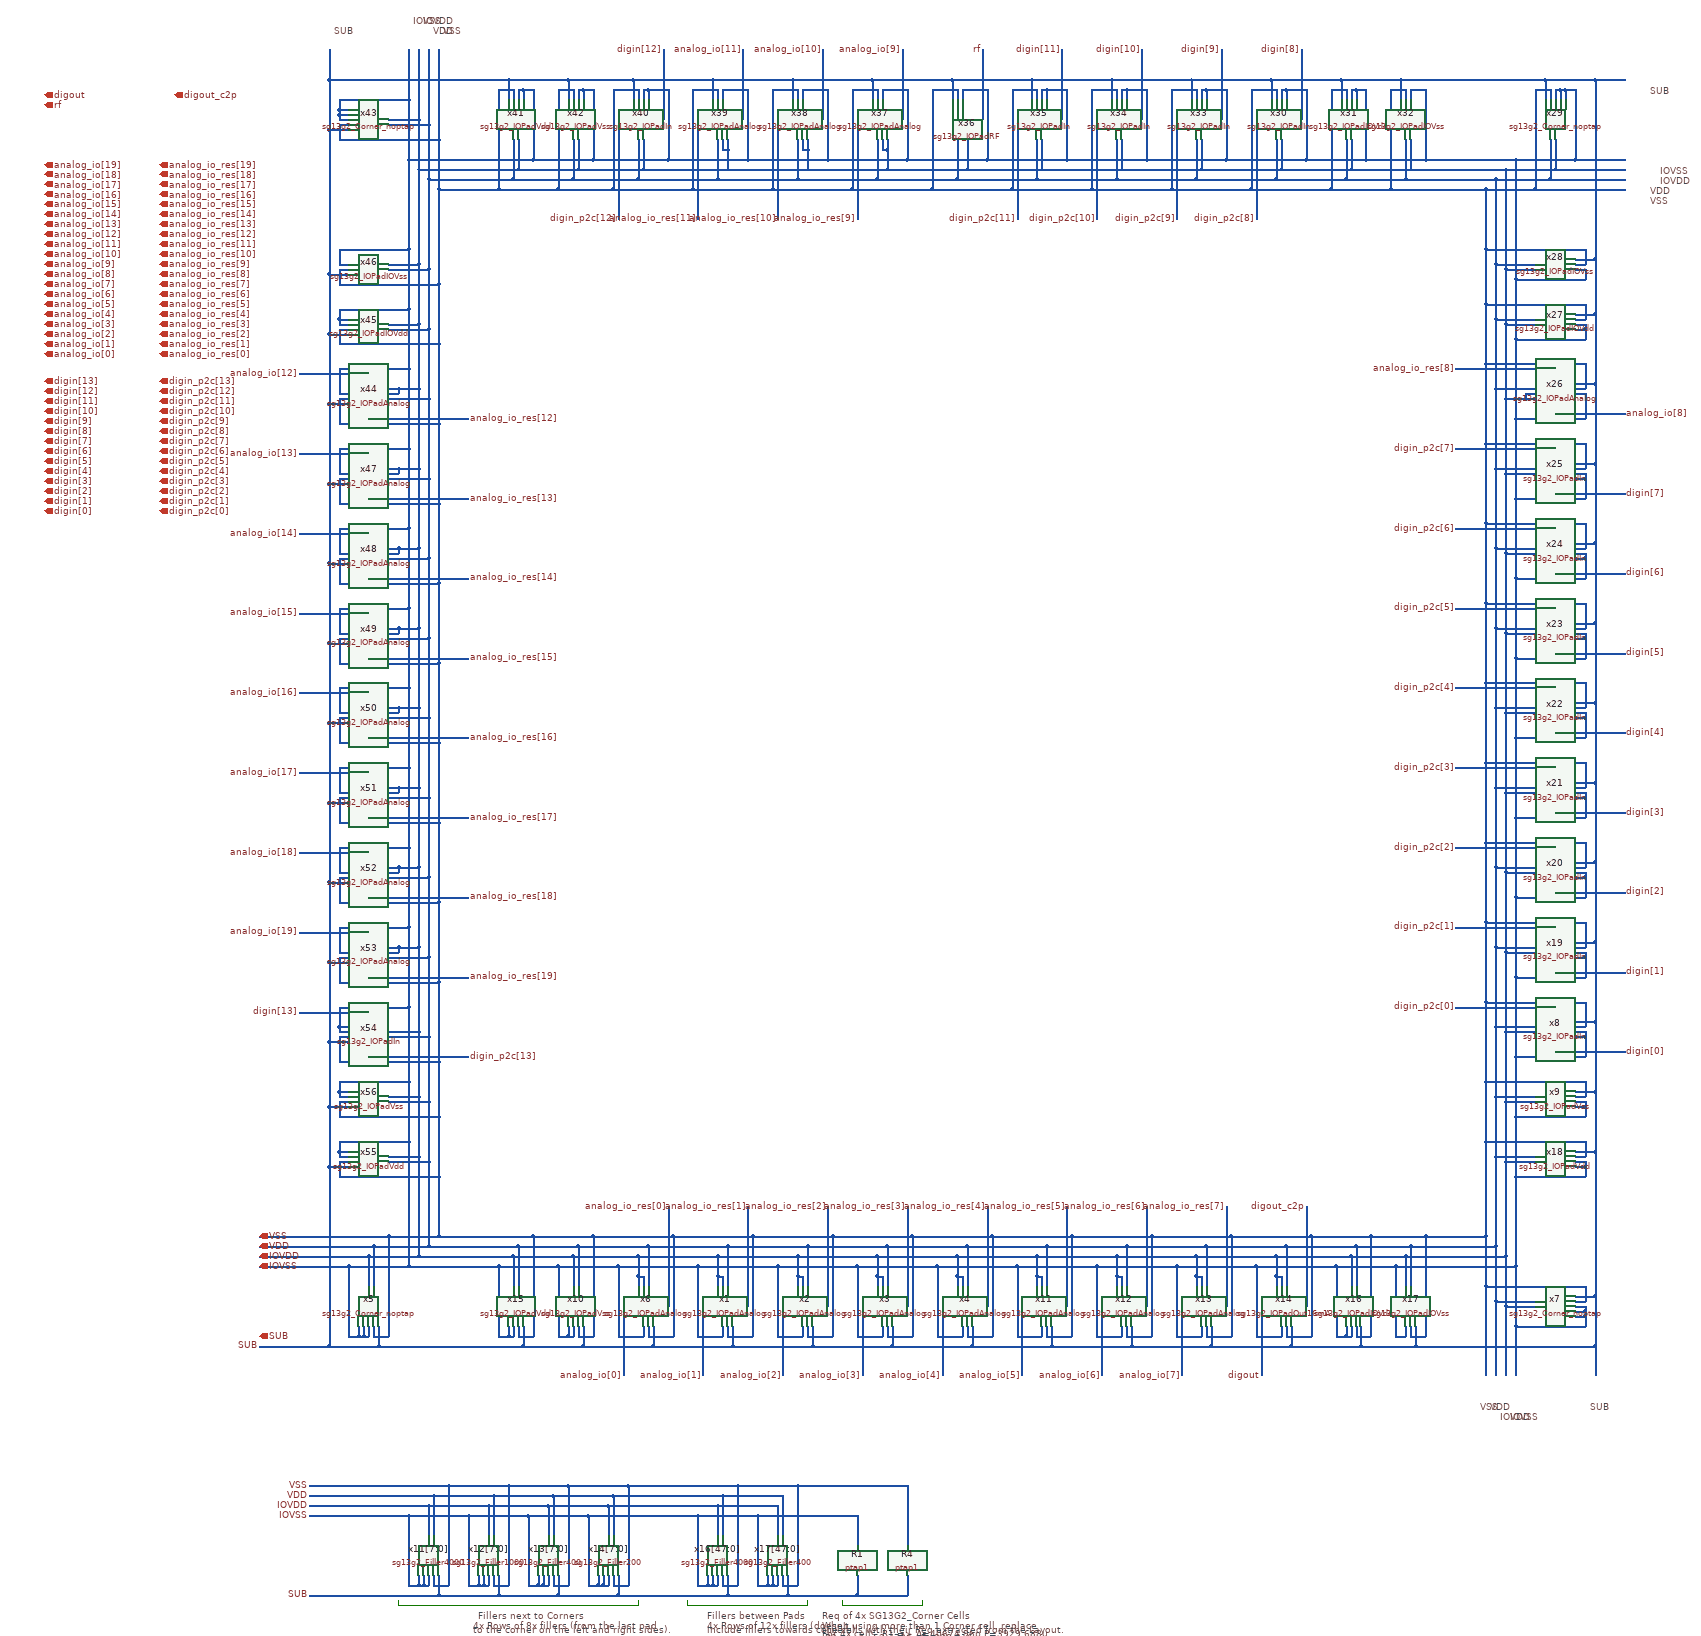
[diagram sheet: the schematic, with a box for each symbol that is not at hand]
v {xschem version=3.4.8RC file_version=1.3}
G {}
K {}
V {}
S {}
F {}
E {}
L 4 1230 430 1230 440 {}
L 4 1230 440 1390 440 {}
L 4 1390 430 1390 440 {}
L 4 920 430 920 440 {}
L 4 920 440 1160 440 {}
L 4 1160 430 1160 440 {}
L 4 340 430 340 440 {}
L 4 340 440 820 440 {}
L 4 820 430 820 440 {}
T {VSS} 2510 30 3 0 0.3 0.3 {}
T {VDD} 2530 30 3 0 0.3 0.3 {}
T {IOVDD} 2550 50 3 0 0.3 0.3 {}
T {IOVSS} 2570 50 3 0 0.3 0.3 {}
T {SUB} 2730 30 3 0 0.3 0.3 {}
T {VSS} 2850 -2390 2 0 0.3 0.3 {}
T {VDD} 2850 -2410 2 0 0.3 0.3 {}
T {IOVDD} 2870 -2430 2 0 0.3 0.3 {}
T {IOVSS} 2870 -2450 2 0 0.3 0.3 {}
T {SUB} 2850 -2610 2 0 0.3 0.3 {}
T {VSS} 430 -2730 1 0 0.3 0.3 {}
T {VDD} 410 -2730 1 0 0.3 0.3 {}
T {IOVDD} 390 -2750 1 0 0.3 0.3 {}
T {IOVSS} 370 -2750 1 0 0.3 0.3 {}
T {SUB} 210 -2730 1 0 0.3 0.3 {}
T {Req of 4x SG13G2_Corner Cells} 1190 450 0 0 0.3 0.3 {}
T {When using more than 1 Corner cell, replace
the cells with their Req extracted from the Layout.
For 4x cells: R1 => A=40674.96p P=3929.688u
              R2 => A=52.7736p P=338.816u} 1190 470 0 0 0.2 0.2 {}
T {Fillers between Pads} 960 450 0 0 0.3 0.3 {}
T {4x Rows of 12x fillers (doesn't
include fillers towards corners).} 960 470 0 0 0.2 0.2 {}
T {Fillers next to Corners} 500 450 0 0 0.3 0.3 {}
T {4x Rows of 8x fillers (from the last pad
to the corner on the left and right sides).} 490 470 0 0 0.2 0.2 {}
N 60 -300 320 -300 {lab=VSS}
N 60 -280 290 -280 {lab=VDD}
N 60 -260 280 -260 {lab=IOVDD}
N 60 -240 240 -240 {lab=IOVSS}
N 200 -80 300 -80 {lab=SUB}
N 300 -120 300 -80 {lab=SUB}
N 260 -120 260 -100 {lab=IOVSS}
N 270 -120 270 -100 {lab=IOVSS}
N 260 -100 270 -100 {lab=IOVSS}
N 290 -120 290 -100 {lab=VSS}
N 290 -100 320 -100 {lab=VSS}
N 320 -300 320 -100 {lab=VSS}
N 290 -280 290 -200 {lab=VDD}
N 280 -260 280 -200 {lab=IOVDD}
N 240 -100 260 -100 {lab=IOVSS}
N 240 -240 240 -100 {lab=IOVSS}
N 280 -120 280 -100 {lab=IOVSS}
N 270 -100 280 -100 {lab=IOVSS}
N 580 -120 580 -100 {lab=VSS}
N 580 -100 610 -100 {lab=VSS}
N 610 -300 610 -100 {lab=VSS}
N 580 -280 580 -200 {lab=VDD}
N 570 -260 570 -200 {lab=IOVDD}
N 420 -300 610 -300 {lab=VSS}
N 400 -280 580 -280 {lab=VDD}
N 380 -260 570 -260 {lab=IOVDD}
N 560 -120 560 -100 {lab=IOVSS}
N 570 -120 570 -100 {lab=IOVSS}
N 560 -100 570 -100 {lab=IOVSS}
N 540 -100 560 -100 {lab=IOVSS}
N 540 -240 540 -100 {lab=IOVSS}
N 360 -240 540 -240 {lab=IOVSS}
N 700 -120 700 -100 {lab=VSS}
N 700 -100 730 -100 {lab=VSS}
N 730 -300 730 -100 {lab=VSS}
N 700 -280 700 -200 {lab=VDD}
N 690 -260 690 -200 {lab=IOVDD}
N 680 -120 680 -100 {lab=IOVSS}
N 690 -120 690 -100 {lab=IOVSS}
N 680 -100 690 -100 {lab=IOVSS}
N 660 -100 680 -100 {lab=IOVSS}
N 660 -240 660 -100 {lab=IOVSS}
N 610 -300 730 -300 {lab=VSS}
N 580 -280 700 -280 {lab=VDD}
N 570 -260 690 -260 {lab=IOVDD}
N 540 -240 660 -240 {lab=IOVSS}
N 2260 -120 2260 -100 {lab=VSS}
N 2260 -100 2290 -100 {lab=VSS}
N 2290 -300 2290 -100 {lab=VSS}
N 2260 -280 2260 -200 {lab=VDD}
N 2250 -260 2250 -200 {lab=IOVDD}
N 2240 -120 2240 -100 {lab=IOVSS}
N 2250 -120 2250 -100 {lab=IOVSS}
N 2240 -100 2250 -100 {lab=IOVSS}
N 2220 -100 2240 -100 {lab=IOVSS}
N 2220 -240 2220 -100 {lab=IOVSS}
N 2170 -300 2290 -300 {lab=VSS}
N 2120 -280 2260 -280 {lab=VDD}
N 2100 -260 2250 -260 {lab=IOVDD}
N 2060 -240 2220 -240 {lab=IOVSS}
N 2370 -120 2370 -100 {lab=VSS}
N 2370 -100 2400 -100 {lab=VSS}
N 2400 -300 2400 -100 {lab=VSS}
N 2360 -260 2360 -200 {lab=IOVDD}
N 2360 -120 2360 -100 {lab=IOVSS}
N 2340 -240 2340 -100 {lab=IOVSS}
N 2290 -300 2400 -300 {lab=VSS}
N 2250 -260 2360 -260 {lab=IOVDD}
N 2220 -240 2340 -240 {lab=IOVSS}
N 2340 -100 2360 -100 {lab=IOVSS}
N 880 -360 880 -160 {lab=analog_io_res[0]}
N 790 -160 790 -20 {lab=analog_io[0]}
N 830 -120 830 -100 {lab=IOVSS}
N 780 -100 830 -100 {lab=IOVSS}
N 780 -240 780 -100 {lab=IOVSS}
N 660 -240 780 -240 {lab=IOVSS}
N 840 -120 840 -100 {lab=VSS}
N 840 -100 890 -100 {lab=VSS}
N 890 -300 890 -100 {lab=VSS}
N 730 -300 890 -300 {lab=VSS}
N 820 -220 820 -200 {lab=IOVDD}
N 690 -260 820 -260 {lab=IOVDD}
N 830 -220 830 -200 {lab=IOVDD}
N 820 -220 830 -220 {lab=IOVDD}
N 820 -260 820 -220 {lab=IOVDD}
N 840 -280 840 -200 {lab=VDD}
N 700 -280 840 -280 {lab=VDD}
N 1040 -360 1040 -160 {lab=analog_io_res[1]}
N 950 -160 950 -20 {lab=analog_io[1]}
N 990 -120 990 -100 {lab=IOVSS}
N 940 -100 990 -100 {lab=IOVSS}
N 940 -240 940 -100 {lab=IOVSS}
N 1000 -120 1000 -100 {lab=VSS}
N 1000 -100 1050 -100 {lab=VSS}
N 1050 -300 1050 -100 {lab=VSS}
N 980 -220 980 -200 {lab=IOVDD}
N 990 -220 990 -200 {lab=IOVDD}
N 980 -220 990 -220 {lab=IOVDD}
N 980 -260 980 -220 {lab=IOVDD}
N 1000 -280 1000 -200 {lab=VDD}
N 780 -240 940 -240 {lab=IOVSS}
N 890 -300 1050 -300 {lab=VSS}
N 820 -260 980 -260 {lab=IOVDD}
N 840 -280 1000 -280 {lab=VDD}
N 1200 -360 1200 -160 {lab=analog_io_res[2]}
N 1110 -160 1110 -20 {lab=analog_io[2]}
N 1150 -120 1150 -100 {lab=IOVSS}
N 1100 -100 1150 -100 {lab=IOVSS}
N 1100 -240 1100 -100 {lab=IOVSS}
N 1160 -120 1160 -100 {lab=VSS}
N 1160 -100 1210 -100 {lab=VSS}
N 1210 -300 1210 -100 {lab=VSS}
N 1140 -220 1140 -200 {lab=IOVDD}
N 1150 -220 1150 -200 {lab=IOVDD}
N 1140 -220 1150 -220 {lab=IOVDD}
N 1140 -260 1140 -220 {lab=IOVDD}
N 1160 -280 1160 -200 {lab=VDD}
N 940 -240 1100 -240 {lab=IOVSS}
N 1050 -300 1210 -300 {lab=VSS}
N 980 -260 1140 -260 {lab=IOVDD}
N 1000 -280 1160 -280 {lab=VDD}
N 1360 -360 1360 -160 {lab=analog_io_res[3]}
N 1270 -160 1270 -20 {lab=analog_io[3]}
N 1310 -120 1310 -100 {lab=IOVSS}
N 1260 -100 1310 -100 {lab=IOVSS}
N 1260 -240 1260 -100 {lab=IOVSS}
N 1320 -120 1320 -100 {lab=VSS}
N 1320 -100 1370 -100 {lab=VSS}
N 1370 -300 1370 -100 {lab=VSS}
N 1300 -220 1300 -200 {lab=IOVDD}
N 1310 -220 1310 -200 {lab=IOVDD}
N 1300 -220 1310 -220 {lab=IOVDD}
N 1300 -260 1300 -220 {lab=IOVDD}
N 1320 -280 1320 -200 {lab=VDD}
N 1100 -240 1260 -240 {lab=IOVSS}
N 1210 -300 1370 -300 {lab=VSS}
N 1140 -260 1300 -260 {lab=IOVDD}
N 1160 -280 1320 -280 {lab=VDD}
N 1520 -360 1520 -160 {lab=analog_io_res[4]}
N 1430 -160 1430 -20 {lab=analog_io[4]}
N 1470 -120 1470 -100 {lab=IOVSS}
N 1420 -100 1470 -100 {lab=IOVSS}
N 1420 -240 1420 -100 {lab=IOVSS}
N 1480 -120 1480 -100 {lab=VSS}
N 1480 -100 1530 -100 {lab=VSS}
N 1530 -300 1530 -100 {lab=VSS}
N 1460 -220 1460 -200 {lab=IOVDD}
N 1470 -220 1470 -200 {lab=IOVDD}
N 1460 -220 1470 -220 {lab=IOVDD}
N 1460 -260 1460 -220 {lab=IOVDD}
N 1480 -280 1480 -200 {lab=VDD}
N 1260 -240 1420 -240 {lab=IOVSS}
N 1370 -300 1530 -300 {lab=VSS}
N 1300 -260 1460 -260 {lab=IOVDD}
N 1320 -280 1480 -280 {lab=VDD}
N 1680 -360 1680 -160 {lab=analog_io_res[5]}
N 1590 -160 1590 -20 {lab=analog_io[5]}
N 1630 -120 1630 -100 {lab=IOVSS}
N 1580 -100 1630 -100 {lab=IOVSS}
N 1580 -240 1580 -100 {lab=IOVSS}
N 1640 -120 1640 -100 {lab=VSS}
N 1640 -100 1690 -100 {lab=VSS}
N 1690 -300 1690 -100 {lab=VSS}
N 1620 -220 1620 -200 {lab=IOVDD}
N 1630 -220 1630 -200 {lab=IOVDD}
N 1620 -220 1630 -220 {lab=IOVDD}
N 1620 -260 1620 -220 {lab=IOVDD}
N 1640 -280 1640 -200 {lab=VDD}
N 1420 -240 1580 -240 {lab=IOVSS}
N 1530 -300 1690 -300 {lab=VSS}
N 1460 -260 1620 -260 {lab=IOVDD}
N 1480 -280 1640 -280 {lab=VDD}
N 1840 -360 1840 -160 {lab=analog_io_res[6]}
N 1750 -160 1750 -20 {lab=analog_io[6]}
N 1790 -120 1790 -100 {lab=IOVSS}
N 1740 -100 1790 -100 {lab=IOVSS}
N 1740 -240 1740 -100 {lab=IOVSS}
N 1800 -120 1800 -100 {lab=VSS}
N 1800 -100 1850 -100 {lab=VSS}
N 1850 -300 1850 -100 {lab=VSS}
N 1780 -220 1780 -200 {lab=IOVDD}
N 1790 -220 1790 -200 {lab=IOVDD}
N 1780 -220 1790 -220 {lab=IOVDD}
N 1800 -280 1800 -200 {lab=VDD}
N 1580 -240 1740 -240 {lab=IOVSS}
N 1690 -300 1850 -300 {lab=VSS}
N 1780 -260 1940 -260 {lab=IOVDD}
N 1640 -280 1800 -280 {lab=VDD}
N 2000 -360 2000 -160 {lab=analog_io_res[7]}
N 1910 -160 1910 -20 {lab=analog_io[7]}
N 1950 -120 1950 -100 {lab=IOVSS}
N 1900 -100 1950 -100 {lab=IOVSS}
N 1900 -240 1900 -100 {lab=IOVSS}
N 1960 -120 1960 -100 {lab=VSS}
N 1960 -100 2010 -100 {lab=VSS}
N 2010 -300 2010 -100 {lab=VSS}
N 1940 -220 1940 -200 {lab=IOVDD}
N 1950 -220 1950 -200 {lab=IOVDD}
N 1940 -220 1950 -220 {lab=IOVDD}
N 1940 -260 1940 -220 {lab=IOVDD}
N 1960 -280 1960 -200 {lab=VDD}
N 1740 -240 1900 -240 {lab=IOVSS}
N 1850 -300 2010 -300 {lab=VSS}
N 1800 -280 1960 -280 {lab=VDD}
N 2160 -360 2160 -160 {lab=digout_c2p}
N 2070 -160 2070 -20 {lab=digout}
N 2110 -120 2110 -100 {lab=IOVSS}
N 2060 -100 2110 -100 {lab=IOVSS}
N 2060 -240 2060 -100 {lab=IOVSS}
N 2120 -120 2120 -100 {lab=VSS}
N 2120 -100 2170 -100 {lab=VSS}
N 2170 -300 2170 -100 {lab=VSS}
N 2100 -220 2100 -200 {lab=IOVDD}
N 2110 -220 2110 -200 {lab=IOVDD}
N 2100 -220 2110 -220 {lab=IOVDD}
N 2100 -260 2100 -220 {lab=IOVDD}
N 2120 -280 2120 -200 {lab=VDD}
N 1900 -240 2060 -240 {lab=IOVSS}
N 2010 -300 2170 -300 {lab=VSS}
N 1940 -260 2100 -260 {lab=IOVDD}
N 1960 -280 2120 -280 {lab=VDD}
N 160 200 440 200 {lab=VSS}
N 160 220 410 220 {lab=VDD}
N 160 240 400 240 {lab=IOVDD}
N 160 260 360 260 {lab=IOVSS}
N 160 420 420 420 {lab=SUB}
N 420 380 420 420 {lab=SUB}
N 380 380 380 400 {lab=IOVSS}
N 390 380 390 400 {lab=IOVSS}
N 380 400 390 400 {lab=IOVSS}
N 410 380 410 400 {lab=VSS}
N 410 400 440 400 {lab=VSS}
N 440 200 440 400 {lab=VSS}
N 410 220 410 300 {lab=VDD}
N 400 240 400 300 {lab=IOVDD}
N 360 400 380 400 {lab=IOVSS}
N 360 260 360 400 {lab=IOVSS}
N 400 380 400 400 {lab=IOVSS}
N 390 400 400 400 {lab=IOVSS}
N 500 380 500 400 {lab=IOVSS}
N 510 380 510 400 {lab=IOVSS}
N 500 400 510 400 {lab=IOVSS}
N 530 380 530 400 {lab=VSS}
N 530 400 560 400 {lab=VSS}
N 560 200 560 400 {lab=VSS}
N 530 220 530 300 {lab=VDD}
N 520 240 520 300 {lab=IOVDD}
N 480 400 500 400 {lab=IOVSS}
N 480 260 480 400 {lab=IOVSS}
N 520 380 520 400 {lab=IOVSS}
N 510 400 520 400 {lab=IOVSS}
N 440 200 560 200 {lab=VSS}
N 410 220 530 220 {lab=VDD}
N 400 240 520 240 {lab=IOVDD}
N 360 260 480 260 {lab=IOVSS}
N 620 380 620 400 {lab=IOVSS}
N 630 380 630 400 {lab=IOVSS}
N 620 400 630 400 {lab=IOVSS}
N 650 380 650 400 {lab=VSS}
N 650 400 680 400 {lab=VSS}
N 680 200 680 400 {lab=VSS}
N 650 220 650 300 {lab=VDD}
N 640 240 640 300 {lab=IOVDD}
N 600 400 620 400 {lab=IOVSS}
N 600 260 600 400 {lab=IOVSS}
N 640 380 640 400 {lab=IOVSS}
N 630 400 640 400 {lab=IOVSS}
N 560 200 680 200 {lab=VSS}
N 530 220 650 220 {lab=VDD}
N 520 240 640 240 {lab=IOVDD}
N 480 260 600 260 {lab=IOVSS}
N 740 380 740 400 {lab=IOVSS}
N 750 380 750 400 {lab=IOVSS}
N 740 400 750 400 {lab=IOVSS}
N 770 380 770 400 {lab=VSS}
N 770 400 800 400 {lab=VSS}
N 800 200 800 400 {lab=VSS}
N 770 220 770 300 {lab=VDD}
N 760 240 760 300 {lab=IOVDD}
N 720 400 740 400 {lab=IOVSS}
N 720 260 720 400 {lab=IOVSS}
N 760 380 760 400 {lab=IOVSS}
N 750 400 760 400 {lab=IOVSS}
N 680 200 800 200 {lab=VSS}
N 650 220 770 220 {lab=VDD}
N 640 240 760 240 {lab=IOVDD}
N 600 260 720 260 {lab=IOVSS}
N 960 380 960 400 {lab=IOVSS}
N 970 380 970 400 {lab=IOVSS}
N 960 400 970 400 {lab=IOVSS}
N 990 380 990 400 {lab=VSS}
N 990 400 1020 400 {lab=VSS}
N 1020 200 1020 400 {lab=VSS}
N 990 220 990 300 {lab=VDD}
N 980 240 980 300 {lab=IOVDD}
N 940 400 960 400 {lab=IOVSS}
N 940 260 940 400 {lab=IOVSS}
N 980 380 980 400 {lab=IOVSS}
N 970 400 980 400 {lab=IOVSS}
N 800 200 1020 200 {lab=VSS}
N 770 220 990 220 {lab=VDD}
N 760 240 980 240 {lab=IOVDD}
N 720 260 940 260 {lab=IOVSS}
N 1080 380 1080 400 {lab=IOVSS}
N 1090 380 1090 400 {lab=IOVSS}
N 1080 400 1090 400 {lab=IOVSS}
N 1110 380 1110 400 {lab=VSS}
N 1110 400 1140 400 {lab=VSS}
N 1140 200 1140 400 {lab=VSS}
N 1110 220 1110 300 {lab=VDD}
N 1100 240 1100 300 {lab=IOVDD}
N 1060 400 1080 400 {lab=IOVSS}
N 1060 260 1060 400 {lab=IOVSS}
N 1100 380 1100 400 {lab=IOVSS}
N 1090 400 1100 400 {lab=IOVSS}
N 1020 200 1140 200 {lab=VSS}
N 990 220 1110 220 {lab=VDD}
N 980 240 1100 240 {lab=IOVDD}
N 940 260 1060 260 {lab=IOVSS}
N 1000 420 1120 420 {lab=SUB}
N 1120 380 1120 420 {lab=SUB}
N 1000 380 1000 420 {lab=SUB}
N 780 420 1000 420 {lab=SUB}
N 780 380 780 420 {lab=SUB}
N 660 420 780 420 {lab=SUB}
N 660 380 660 420 {lab=SUB}
N 540 420 660 420 {lab=SUB}
N 540 380 540 420 {lab=SUB}
N 420 420 540 420 {lab=SUB}
N 2270 -80 2380 -80 {lab=SUB}
N 2380 -120 2380 -80 {lab=SUB}
N 2270 -120 2270 -80 {lab=SUB}
N 2130 -80 2270 -80 {lab=SUB}
N 2130 -120 2130 -80 {lab=SUB}
N 1970 -80 2130 -80 {lab=SUB}
N 1970 -120 1970 -80 {lab=SUB}
N 1810 -80 1970 -80 {lab=SUB}
N 1810 -120 1810 -80 {lab=SUB}
N 1650 -80 1810 -80 {lab=SUB}
N 1650 -120 1650 -80 {lab=SUB}
N 1490 -80 1650 -80 {lab=SUB}
N 1490 -120 1490 -80 {lab=SUB}
N 1330 -80 1490 -80 {lab=SUB}
N 1330 -120 1330 -80 {lab=SUB}
N 1170 -80 1330 -80 {lab=SUB}
N 1170 -120 1170 -80 {lab=SUB}
N 1010 -80 1170 -80 {lab=SUB}
N 1010 -120 1010 -80 {lab=SUB}
N 850 -80 1010 -80 {lab=SUB}
N 850 -120 850 -80 {lab=SUB}
N 710 -80 850 -80 {lab=SUB}
N 710 -120 710 -80 {lab=SUB}
N 590 -80 710 -80 {lab=SUB}
N 590 -120 590 -80 {lab=SUB}
N 300 -80 590 -80 {lab=SUB}
N 2370 -280 2370 -200 {lab=VDD}
N 2260 -280 2370 -280 {lab=VDD}
N 1780 -260 1780 -220 {lab=IOVDD}
N 1620 -260 1780 -260 {lab=IOVDD}
N 2520 -200 2520 -20 {lab=VSS}
N 2540 -170 2540 -20 {lab=VDD}
N 2560 -160 2560 -20 {lab=IOVDD}
N 2580 -120 2580 -20 {lab=IOVSS}
N 2740 -80 2740 -20 {lab=SUB}
N 2700 -180 2740 -180 {lab=SUB}
N 2700 -140 2720 -140 {lab=IOVSS}
N 2700 -150 2720 -150 {lab=IOVSS}
N 2720 -150 2720 -140 {lab=IOVSS}
N 2700 -170 2720 -170 {lab=VSS}
N 2720 -200 2720 -170 {lab=VSS}
N 2520 -200 2720 -200 {lab=VSS}
N 2540 -170 2620 -170 {lab=VDD}
N 2560 -160 2620 -160 {lab=IOVDD}
N 2720 -140 2720 -120 {lab=IOVSS}
N 2580 -120 2720 -120 {lab=IOVSS}
N 2700 -160 2720 -160 {lab=IOVSS}
N 2720 -160 2720 -150 {lab=IOVSS}
N 2700 -460 2720 -460 {lab=VSS}
N 2720 -490 2720 -460 {lab=VSS}
N 2520 -490 2720 -490 {lab=VSS}
N 2540 -460 2620 -460 {lab=VDD}
N 2560 -450 2620 -450 {lab=IOVDD}
N 2520 -300 2520 -200 {lab=VSS}
N 2540 -280 2540 -170 {lab=VDD}
N 2560 -260 2560 -160 {lab=IOVDD}
N 2700 -440 2720 -440 {lab=IOVSS}
N 2700 -450 2720 -450 {lab=IOVSS}
N 2720 -450 2720 -440 {lab=IOVSS}
N 2720 -440 2720 -420 {lab=IOVSS}
N 2580 -420 2720 -420 {lab=IOVSS}
N 2580 -240 2580 -120 {lab=IOVSS}
N 2700 -580 2720 -580 {lab=VSS}
N 2720 -610 2720 -580 {lab=VSS}
N 2520 -610 2720 -610 {lab=VSS}
N 2540 -580 2620 -580 {lab=VDD}
N 2560 -570 2620 -570 {lab=IOVDD}
N 2700 -560 2720 -560 {lab=IOVSS}
N 2700 -570 2720 -570 {lab=IOVSS}
N 2720 -570 2720 -560 {lab=IOVSS}
N 2720 -560 2720 -540 {lab=IOVSS}
N 2580 -540 2720 -540 {lab=IOVSS}
N 2520 -610 2520 -490 {lab=VSS}
N 2540 -580 2540 -460 {lab=VDD}
N 2560 -570 2560 -450 {lab=IOVDD}
N 2580 -540 2580 -420 {lab=IOVSS}
N 2700 -2140 2720 -2140 {lab=VSS}
N 2720 -2170 2720 -2140 {lab=VSS}
N 2520 -2170 2720 -2170 {lab=VSS}
N 2540 -2140 2620 -2140 {lab=VDD}
N 2560 -2130 2620 -2130 {lab=IOVDD}
N 2700 -2120 2720 -2120 {lab=IOVSS}
N 2700 -2130 2720 -2130 {lab=IOVSS}
N 2720 -2130 2720 -2120 {lab=IOVSS}
N 2720 -2120 2720 -2100 {lab=IOVSS}
N 2580 -2100 2720 -2100 {lab=IOVSS}
N 2520 -2170 2520 -2050 {lab=VSS}
N 2540 -2140 2540 -2000 {lab=VDD}
N 2560 -2130 2560 -1980 {lab=IOVDD}
N 2580 -2100 2580 -1940 {lab=IOVSS}
N 2700 -2250 2720 -2250 {lab=VSS}
N 2720 -2280 2720 -2250 {lab=VSS}
N 2520 -2280 2720 -2280 {lab=VSS}
N 2560 -2240 2620 -2240 {lab=IOVDD}
N 2700 -2240 2720 -2240 {lab=IOVSS}
N 2580 -2220 2720 -2220 {lab=IOVSS}
N 2520 -2280 2520 -2170 {lab=VSS}
N 2560 -2240 2560 -2130 {lab=IOVDD}
N 2580 -2220 2580 -2100 {lab=IOVSS}
N 2720 -2240 2720 -2220 {lab=IOVSS}
N 2460 -760 2660 -760 {lab=digin_p2c[0]}
N 2660 -670 2800 -670 {lab=digin[0]}
N 2700 -710 2720 -710 {lab=IOVSS}
N 2720 -700 2720 -660 {lab=IOVSS}
N 2580 -660 2720 -660 {lab=IOVSS}
N 2580 -660 2580 -540 {lab=IOVSS}
N 2700 -720 2720 -720 {lab=VSS}
N 2720 -770 2720 -720 {lab=VSS}
N 2520 -770 2720 -770 {lab=VSS}
N 2520 -770 2520 -610 {lab=VSS}
N 2560 -710 2620 -710 {lab=IOVDD}
N 2540 -720 2620 -720 {lab=VDD}
N 2540 -720 2540 -580 {lab=VDD}
N 2460 -920 2660 -920 {lab=digin_p2c[1]}
N 2660 -830 2800 -830 {lab=digin[1]}
N 2700 -870 2720 -870 {lab=IOVSS}
N 2720 -860 2720 -820 {lab=IOVSS}
N 2580 -820 2720 -820 {lab=IOVSS}
N 2700 -880 2720 -880 {lab=VSS}
N 2720 -930 2720 -880 {lab=VSS}
N 2520 -930 2720 -930 {lab=VSS}
N 2560 -870 2620 -870 {lab=IOVDD}
N 2540 -880 2620 -880 {lab=VDD}
N 2580 -820 2580 -660 {lab=IOVSS}
N 2520 -930 2520 -770 {lab=VSS}
N 2560 -710 2560 -570 {lab=IOVDD}
N 2540 -880 2540 -720 {lab=VDD}
N 2460 -1080 2660 -1080 {lab=digin_p2c[2]}
N 2660 -990 2800 -990 {lab=digin[2]}
N 2700 -1030 2720 -1030 {lab=IOVSS}
N 2720 -1020 2720 -980 {lab=IOVSS}
N 2580 -980 2720 -980 {lab=IOVSS}
N 2700 -1040 2720 -1040 {lab=VSS}
N 2720 -1090 2720 -1040 {lab=VSS}
N 2520 -1090 2720 -1090 {lab=VSS}
N 2560 -1030 2620 -1030 {lab=IOVDD}
N 2540 -1040 2620 -1040 {lab=VDD}
N 2580 -980 2580 -820 {lab=IOVSS}
N 2520 -1090 2520 -930 {lab=VSS}
N 2560 -870 2560 -710 {lab=IOVDD}
N 2540 -1040 2540 -880 {lab=VDD}
N 2460 -1240 2660 -1240 {lab=digin_p2c[3]}
N 2660 -1150 2800 -1150 {lab=digin[3]}
N 2700 -1190 2720 -1190 {lab=IOVSS}
N 2720 -1180 2720 -1140 {lab=IOVSS}
N 2580 -1140 2720 -1140 {lab=IOVSS}
N 2700 -1200 2720 -1200 {lab=VSS}
N 2720 -1250 2720 -1200 {lab=VSS}
N 2520 -1250 2720 -1250 {lab=VSS}
N 2560 -1190 2620 -1190 {lab=IOVDD}
N 2540 -1200 2620 -1200 {lab=VDD}
N 2580 -1140 2580 -980 {lab=IOVSS}
N 2520 -1250 2520 -1090 {lab=VSS}
N 2560 -1030 2560 -870 {lab=IOVDD}
N 2540 -1200 2540 -1040 {lab=VDD}
N 2460 -1400 2660 -1400 {lab=digin_p2c[4]}
N 2660 -1310 2800 -1310 {lab=digin[4]}
N 2700 -1350 2720 -1350 {lab=IOVSS}
N 2720 -1340 2720 -1300 {lab=IOVSS}
N 2580 -1300 2720 -1300 {lab=IOVSS}
N 2700 -1360 2720 -1360 {lab=VSS}
N 2720 -1410 2720 -1360 {lab=VSS}
N 2520 -1410 2720 -1410 {lab=VSS}
N 2560 -1350 2620 -1350 {lab=IOVDD}
N 2540 -1360 2620 -1360 {lab=VDD}
N 2580 -1300 2580 -1140 {lab=IOVSS}
N 2520 -1410 2520 -1250 {lab=VSS}
N 2560 -1190 2560 -1030 {lab=IOVDD}
N 2540 -1360 2540 -1200 {lab=VDD}
N 2460 -1560 2660 -1560 {lab=digin_p2c[5]}
N 2660 -1470 2800 -1470 {lab=digin[5]}
N 2700 -1510 2720 -1510 {lab=IOVSS}
N 2720 -1500 2720 -1460 {lab=IOVSS}
N 2580 -1460 2720 -1460 {lab=IOVSS}
N 2700 -1520 2720 -1520 {lab=VSS}
N 2720 -1570 2720 -1520 {lab=VSS}
N 2520 -1570 2720 -1570 {lab=VSS}
N 2560 -1510 2620 -1510 {lab=IOVDD}
N 2540 -1520 2620 -1520 {lab=VDD}
N 2580 -1460 2580 -1300 {lab=IOVSS}
N 2520 -1570 2520 -1410 {lab=VSS}
N 2560 -1350 2560 -1190 {lab=IOVDD}
N 2540 -1520 2540 -1360 {lab=VDD}
N 2460 -1720 2660 -1720 {lab=digin_p2c[6]}
N 2660 -1630 2800 -1630 {lab=digin[6]}
N 2700 -1670 2720 -1670 {lab=IOVSS}
N 2720 -1660 2720 -1620 {lab=IOVSS}
N 2580 -1620 2720 -1620 {lab=IOVSS}
N 2700 -1680 2720 -1680 {lab=VSS}
N 2720 -1730 2720 -1680 {lab=VSS}
N 2520 -1730 2720 -1730 {lab=VSS}
N 2540 -1680 2620 -1680 {lab=VDD}
N 2580 -1620 2580 -1460 {lab=IOVSS}
N 2520 -1730 2520 -1570 {lab=VSS}
N 2560 -1670 2560 -1510 {lab=IOVDD}
N 2540 -1680 2540 -1520 {lab=VDD}
N 2460 -1880 2660 -1880 {lab=digin_p2c[7]}
N 2660 -1790 2800 -1790 {lab=digin[7]}
N 2700 -1830 2720 -1830 {lab=IOVSS}
N 2720 -1820 2720 -1780 {lab=IOVSS}
N 2580 -1780 2720 -1780 {lab=IOVSS}
N 2700 -1840 2720 -1840 {lab=VSS}
N 2720 -1890 2720 -1840 {lab=VSS}
N 2520 -1890 2720 -1890 {lab=VSS}
N 2560 -1830 2620 -1830 {lab=IOVDD}
N 2540 -1840 2620 -1840 {lab=VDD}
N 2580 -1780 2580 -1620 {lab=IOVSS}
N 2520 -1890 2520 -1730 {lab=VSS}
N 2540 -1840 2540 -1680 {lab=VDD}
N 2460 -2040 2660 -2040 {lab=analog_io_res[8]}
N 2660 -1950 2800 -1950 {lab=analog_io[8]}
N 2700 -1990 2720 -1990 {lab=IOVSS}
N 2720 -1990 2720 -1940 {lab=IOVSS}
N 2580 -1940 2720 -1940 {lab=IOVSS}
N 2700 -2000 2720 -2000 {lab=VSS}
N 2720 -2050 2720 -2000 {lab=VSS}
N 2520 -2050 2720 -2050 {lab=VSS}
N 2600 -1980 2620 -1980 {lab=IOVDD}
N 2600 -1990 2620 -1990 {lab=IOVDD}
N 2600 -1990 2600 -1980 {lab=IOVDD}
N 2560 -1980 2600 -1980 {lab=IOVDD}
N 2540 -2000 2620 -2000 {lab=VDD}
N 2580 -1940 2580 -1780 {lab=IOVSS}
N 2520 -2050 2520 -1890 {lab=VSS}
N 2560 -1830 2560 -1670 {lab=IOVDD}
N 2540 -2000 2540 -1840 {lab=VDD}
N 2740 -2260 2740 -2150 {lab=SUB}
N 2700 -2260 2740 -2260 {lab=SUB}
N 2700 -2150 2740 -2150 {lab=SUB}
N 2740 -2150 2740 -2010 {lab=SUB}
N 2700 -2010 2740 -2010 {lab=SUB}
N 2740 -2010 2740 -1850 {lab=SUB}
N 2700 -1850 2740 -1850 {lab=SUB}
N 2740 -1850 2740 -1690 {lab=SUB}
N 2700 -1690 2740 -1690 {lab=SUB}
N 2740 -1690 2740 -1530 {lab=SUB}
N 2700 -1530 2740 -1530 {lab=SUB}
N 2740 -1530 2740 -1370 {lab=SUB}
N 2700 -1370 2740 -1370 {lab=SUB}
N 2740 -1370 2740 -1210 {lab=SUB}
N 2700 -1210 2740 -1210 {lab=SUB}
N 2740 -1210 2740 -1050 {lab=SUB}
N 2700 -1050 2740 -1050 {lab=SUB}
N 2740 -1050 2740 -890 {lab=SUB}
N 2700 -890 2740 -890 {lab=SUB}
N 2740 -890 2740 -730 {lab=SUB}
N 2700 -730 2740 -730 {lab=SUB}
N 2740 -730 2740 -590 {lab=SUB}
N 2700 -590 2740 -590 {lab=SUB}
N 2740 -590 2740 -470 {lab=SUB}
N 2700 -470 2740 -470 {lab=SUB}
N 2740 -470 2740 -180 {lab=SUB}
N 2540 -2250 2620 -2250 {lab=VDD}
N 2540 -2250 2540 -2140 {lab=VDD}
N 2560 -1670 2620 -1670 {lab=IOVDD}
N 2560 -1510 2560 -1350 {lab=IOVDD}
N 2400 -300 2520 -300 {lab=VSS}
N 2520 -490 2520 -300 {lab=VSS}
N 2370 -280 2540 -280 {lab=VDD}
N 2540 -460 2540 -280 {lab=VDD}
N 2360 -260 2560 -260 {lab=IOVDD}
N 2560 -450 2560 -260 {lab=IOVDD}
N 2340 -240 2580 -240 {lab=IOVSS}
N 2580 -420 2580 -240 {lab=IOVSS}
N 2380 -80 2740 -80 {lab=SUB}
N 2740 -180 2740 -80 {lab=SUB}
N 2620 -2400 2800 -2400 {lab=VSS}
N 2650 -2420 2800 -2420 {lab=VDD}
N 2660 -2440 2800 -2440 {lab=IOVDD}
N 2700 -2460 2800 -2460 {lab=IOVSS}
N 2640 -2620 2640 -2580 {lab=SUB}
N 2680 -2600 2680 -2580 {lab=IOVSS}
N 2670 -2600 2670 -2580 {lab=IOVSS}
N 2670 -2600 2680 -2600 {lab=IOVSS}
N 2650 -2600 2650 -2580 {lab=VSS}
N 2620 -2600 2650 -2600 {lab=VSS}
N 2620 -2600 2620 -2400 {lab=VSS}
N 2650 -2500 2650 -2420 {lab=VDD}
N 2660 -2500 2660 -2440 {lab=IOVDD}
N 2680 -2600 2700 -2600 {lab=IOVSS}
N 2700 -2600 2700 -2460 {lab=IOVSS}
N 2660 -2600 2660 -2580 {lab=IOVSS}
N 2660 -2600 2670 -2600 {lab=IOVSS}
N 2360 -2600 2360 -2580 {lab=VSS}
N 2330 -2600 2360 -2600 {lab=VSS}
N 2330 -2600 2330 -2400 {lab=VSS}
N 2360 -2500 2360 -2420 {lab=VDD}
N 2370 -2500 2370 -2440 {lab=IOVDD}
N 2370 -2600 2370 -2580 {lab=IOVSS}
N 2370 -2600 2400 -2600 {lab=IOVSS}
N 2400 -2600 2400 -2460 {lab=IOVSS}
N 2240 -2600 2240 -2580 {lab=VSS}
N 2210 -2600 2240 -2600 {lab=VSS}
N 2210 -2600 2210 -2400 {lab=VSS}
N 2240 -2500 2240 -2420 {lab=VDD}
N 2250 -2500 2250 -2440 {lab=IOVDD}
N 2260 -2600 2260 -2580 {lab=IOVSS}
N 2250 -2600 2250 -2580 {lab=IOVSS}
N 2250 -2600 2260 -2600 {lab=IOVSS}
N 2260 -2600 2280 -2600 {lab=IOVSS}
N 2280 -2600 2280 -2460 {lab=IOVSS}
N 2210 -2400 2330 -2400 {lab=VSS}
N 2240 -2420 2360 -2420 {lab=VDD}
N 2250 -2440 2370 -2440 {lab=IOVDD}
N 2280 -2460 2400 -2460 {lab=IOVSS}
N 570 -2600 570 -2580 {lab=VSS}
N 540 -2600 570 -2600 {lab=VSS}
N 540 -2600 540 -2400 {lab=VSS}
N 570 -2500 570 -2420 {lab=VDD}
N 580 -2500 580 -2440 {lab=IOVDD}
N 590 -2600 590 -2580 {lab=IOVSS}
N 580 -2600 580 -2580 {lab=IOVSS}
N 580 -2600 590 -2600 {lab=IOVSS}
N 590 -2600 610 -2600 {lab=IOVSS}
N 610 -2600 610 -2460 {lab=IOVSS}
N 690 -2600 690 -2580 {lab=VSS}
N 660 -2600 690 -2600 {lab=VSS}
N 660 -2600 660 -2400 {lab=VSS}
N 700 -2500 700 -2440 {lab=IOVDD}
N 700 -2600 700 -2580 {lab=IOVSS}
N 730 -2600 730 -2460 {lab=IOVSS}
N 660 -2400 770 -2400 {lab=VSS}
N 830 -2440 1000 -2440 {lab=IOVDD}
N 730 -2460 880 -2460 {lab=IOVSS}
N 710 -2600 730 -2600 {lab=IOVSS}
N 2060 -2540 2060 -2340 {lab=digin_p2c[8]}
N 2110 -2600 2110 -2580 {lab=IOVSS}
N 2120 -2600 2160 -2600 {lab=IOVSS}
N 2160 -2600 2160 -2460 {lab=IOVSS}
N 2160 -2460 2280 -2460 {lab=IOVSS}
N 2100 -2600 2100 -2580 {lab=VSS}
N 2050 -2600 2100 -2600 {lab=VSS}
N 2050 -2600 2050 -2400 {lab=VSS}
N 2050 -2400 2210 -2400 {lab=VSS}
N 2110 -2500 2110 -2440 {lab=IOVDD}
N 2100 -2500 2100 -2420 {lab=VDD}
N 2100 -2420 2240 -2420 {lab=VDD}
N 1900 -2540 1900 -2340 {lab=digin_p2c[9]}
N 1990 -2680 1990 -2540 {lab=digin[9]}
N 1950 -2600 1950 -2580 {lab=IOVSS}
N 1960 -2600 2000 -2600 {lab=IOVSS}
N 2000 -2600 2000 -2460 {lab=IOVSS}
N 1940 -2600 1940 -2580 {lab=VSS}
N 1890 -2600 1940 -2600 {lab=VSS}
N 1890 -2600 1890 -2400 {lab=VSS}
N 1950 -2500 1950 -2440 {lab=IOVDD}
N 1940 -2500 1940 -2420 {lab=VDD}
N 2000 -2460 2160 -2460 {lab=IOVSS}
N 1890 -2400 2050 -2400 {lab=VSS}
N 1940 -2420 2100 -2420 {lab=VDD}
N 1740 -2540 1740 -2340 {lab=digin_p2c[10]}
N 1830 -2680 1830 -2540 {lab=digin[10]}
N 1790 -2600 1790 -2580 {lab=IOVSS}
N 1800 -2600 1840 -2600 {lab=IOVSS}
N 1840 -2600 1840 -2460 {lab=IOVSS}
N 1780 -2600 1780 -2580 {lab=VSS}
N 1730 -2600 1780 -2600 {lab=VSS}
N 1730 -2600 1730 -2400 {lab=VSS}
N 1790 -2500 1790 -2440 {lab=IOVDD}
N 1780 -2500 1780 -2420 {lab=VDD}
N 1840 -2460 2000 -2460 {lab=IOVSS}
N 1730 -2400 1890 -2400 {lab=VSS}
N 2110 -2440 2250 -2440 {lab=IOVDD}
N 1780 -2420 1940 -2420 {lab=VDD}
N 1580 -2540 1580 -2340 {lab=digin_p2c[11]}
N 1670 -2680 1670 -2540 {lab=digin[11]}
N 1630 -2600 1630 -2580 {lab=IOVSS}
N 1640 -2600 1680 -2600 {lab=IOVSS}
N 1680 -2600 1680 -2460 {lab=IOVSS}
N 1620 -2600 1620 -2580 {lab=VSS}
N 1570 -2600 1620 -2600 {lab=VSS}
N 1570 -2600 1570 -2400 {lab=VSS}
N 1630 -2500 1630 -2440 {lab=IOVDD}
N 1620 -2500 1620 -2420 {lab=VDD}
N 1680 -2460 1840 -2460 {lab=IOVSS}
N 1570 -2400 1730 -2400 {lab=VSS}
N 1790 -2440 1950 -2440 {lab=IOVDD}
N 1620 -2420 1780 -2420 {lab=VDD}
N 1510 -2680 1510 -2540 {lab=rf}
N 1470 -2600 1470 -2580 {lab=IOVSS}
N 1470 -2600 1520 -2600 {lab=IOVSS}
N 1520 -2600 1520 -2460 {lab=IOVSS}
N 1460 -2600 1460 -2580 {lab=VSS}
N 1410 -2600 1460 -2600 {lab=VSS}
N 1410 -2600 1410 -2400 {lab=VSS}
N 1480 -2500 1480 -2440 {lab=IOVDD}
N 1460 -2500 1460 -2420 {lab=VDD}
N 1520 -2460 1680 -2460 {lab=IOVSS}
N 1410 -2400 1570 -2400 {lab=VSS}
N 1630 -2440 1790 -2440 {lab=IOVDD}
N 1460 -2420 1620 -2420 {lab=VDD}
N 1260 -2540 1260 -2340 {lab=analog_io_res[9]}
N 1350 -2680 1350 -2540 {lab=analog_io[9]}
N 1310 -2600 1310 -2580 {lab=IOVSS}
N 1310 -2600 1360 -2600 {lab=IOVSS}
N 1360 -2600 1360 -2460 {lab=IOVSS}
N 1300 -2600 1300 -2580 {lab=VSS}
N 1250 -2600 1300 -2600 {lab=VSS}
N 1250 -2600 1250 -2400 {lab=VSS}
N 1320 -2500 1320 -2480 {lab=IOVDD}
N 1310 -2500 1310 -2480 {lab=IOVDD}
N 1310 -2480 1320 -2480 {lab=IOVDD}
N 1320 -2480 1320 -2440 {lab=IOVDD}
N 1300 -2500 1300 -2420 {lab=VDD}
N 1360 -2460 1520 -2460 {lab=IOVSS}
N 1250 -2400 1410 -2400 {lab=VSS}
N 1320 -2440 1480 -2440 {lab=IOVDD}
N 1300 -2420 1460 -2420 {lab=VDD}
N 1100 -2540 1100 -2340 {lab=analog_io_res[10]}
N 1190 -2680 1190 -2540 {lab=analog_io[10]}
N 1150 -2600 1150 -2580 {lab=IOVSS}
N 1150 -2600 1200 -2600 {lab=IOVSS}
N 1200 -2600 1200 -2460 {lab=IOVSS}
N 1140 -2600 1140 -2580 {lab=VSS}
N 1090 -2600 1140 -2600 {lab=VSS}
N 1090 -2600 1090 -2400 {lab=VSS}
N 1160 -2500 1160 -2480 {lab=IOVDD}
N 1150 -2500 1150 -2480 {lab=IOVDD}
N 1150 -2480 1160 -2480 {lab=IOVDD}
N 1140 -2500 1140 -2420 {lab=VDD}
N 1200 -2460 1360 -2460 {lab=IOVSS}
N 1090 -2400 1250 -2400 {lab=VSS}
N 1000 -2440 1160 -2440 {lab=IOVDD}
N 1140 -2420 1300 -2420 {lab=VDD}
N 940 -2540 940 -2340 {lab=analog_io_res[11]}
N 1030 -2680 1030 -2540 {lab=analog_io[11]}
N 990 -2600 990 -2580 {lab=IOVSS}
N 990 -2600 1040 -2600 {lab=IOVSS}
N 1040 -2600 1040 -2460 {lab=IOVSS}
N 980 -2600 980 -2580 {lab=VSS}
N 930 -2600 980 -2600 {lab=VSS}
N 930 -2600 930 -2400 {lab=VSS}
N 1000 -2500 1000 -2480 {lab=IOVDD}
N 990 -2500 990 -2480 {lab=IOVDD}
N 990 -2480 1000 -2480 {lab=IOVDD}
N 1000 -2480 1000 -2440 {lab=IOVDD}
N 980 -2500 980 -2420 {lab=VDD}
N 1040 -2460 1200 -2460 {lab=IOVSS}
N 930 -2400 1090 -2400 {lab=VSS}
N 980 -2420 1140 -2420 {lab=VDD}
N 780 -2540 780 -2340 {lab=digin_p2c[12]}
N 870 -2680 870 -2540 {lab=digin[12]}
N 830 -2600 830 -2580 {lab=IOVSS}
N 840 -2600 880 -2600 {lab=IOVSS}
N 880 -2600 880 -2460 {lab=IOVSS}
N 820 -2600 820 -2580 {lab=VSS}
N 770 -2600 820 -2600 {lab=VSS}
N 770 -2600 770 -2400 {lab=VSS}
N 830 -2500 830 -2440 {lab=IOVDD}
N 820 -2500 820 -2420 {lab=VDD}
N 880 -2460 1040 -2460 {lab=IOVSS}
N 770 -2400 930 -2400 {lab=VSS}
N 820 -2420 980 -2420 {lab=VDD}
N 680 -2620 810 -2620 {lab=SUB}
N 680 -2620 680 -2580 {lab=SUB}
N 560 -2620 560 -2580 {lab=SUB}
N 810 -2620 810 -2580 {lab=SUB}
N 810 -2620 970 -2620 {lab=SUB}
N 970 -2620 970 -2580 {lab=SUB}
N 970 -2620 1130 -2620 {lab=SUB}
N 1130 -2620 1130 -2580 {lab=SUB}
N 1130 -2620 1290 -2620 {lab=SUB}
N 1290 -2620 1290 -2580 {lab=SUB}
N 1290 -2620 1450 -2620 {lab=SUB}
N 1450 -2620 1450 -2580 {lab=SUB}
N 1450 -2620 1610 -2620 {lab=SUB}
N 1610 -2620 1610 -2580 {lab=SUB}
N 1610 -2620 1770 -2620 {lab=SUB}
N 1770 -2620 1770 -2580 {lab=SUB}
N 1770 -2620 1930 -2620 {lab=SUB}
N 1930 -2620 1930 -2580 {lab=SUB}
N 1930 -2620 2090 -2620 {lab=SUB}
N 2090 -2620 2090 -2580 {lab=SUB}
N 2090 -2620 2230 -2620 {lab=SUB}
N 2230 -2620 2230 -2580 {lab=SUB}
N 2230 -2620 2350 -2620 {lab=SUB}
N 2350 -2620 2350 -2580 {lab=SUB}
N 2350 -2620 2640 -2620 {lab=SUB}
N 690 -2500 690 -2420 {lab=VDD}
N 690 -2420 820 -2420 {lab=VDD}
N 1160 -2480 1160 -2440 {lab=IOVDD}
N 1160 -2440 1320 -2440 {lab=IOVDD}
N 2520 -2400 2620 -2400 {lab=VSS}
N 2540 -2420 2650 -2420 {lab=VDD}
N 2560 -2440 2660 -2440 {lab=IOVDD}
N 2580 -2460 2700 -2460 {lab=IOVSS}
N 2740 -2620 2800 -2620 {lab=SUB}
N 2740 -2620 2740 -2260 {lab=SUB}
N 2640 -2620 2740 -2620 {lab=SUB}
N 2520 -2400 2520 -2280 {lab=VSS}
N 2330 -2400 2520 -2400 {lab=VSS}
N 2540 -2420 2540 -2250 {lab=VDD}
N 2360 -2420 2540 -2420 {lab=VDD}
N 2560 -2440 2560 -2240 {lab=IOVDD}
N 2370 -2440 2560 -2440 {lab=IOVDD}
N 2580 -2460 2580 -2220 {lab=IOVSS}
N 2400 -2460 2580 -2460 {lab=IOVSS}
N 540 -2400 660 -2400 {lab=VSS}
N 580 -2440 700 -2440 {lab=IOVDD}
N 610 -2460 730 -2460 {lab=IOVSS}
N 560 -2620 680 -2620 {lab=SUB}
N 570 -2420 690 -2420 {lab=VDD}
N 420 -2680 420 -2500 {lab=VSS}
N 400 -2680 400 -2530 {lab=VDD}
N 380 -2680 380 -2540 {lab=IOVDD}
N 360 -2680 360 -2580 {lab=IOVSS}
N 200 -2520 240 -2520 {lab=SUB}
N 220 -2560 240 -2560 {lab=IOVSS}
N 220 -2550 240 -2550 {lab=IOVSS}
N 220 -2560 220 -2550 {lab=IOVSS}
N 220 -2530 240 -2530 {lab=VSS}
N 220 -2530 220 -2500 {lab=VSS}
N 220 -2500 420 -2500 {lab=VSS}
N 320 -2530 400 -2530 {lab=VDD}
N 320 -2540 380 -2540 {lab=IOVDD}
N 220 -2580 220 -2560 {lab=IOVSS}
N 220 -2580 360 -2580 {lab=IOVSS}
N 220 -2540 240 -2540 {lab=IOVSS}
N 220 -2550 220 -2540 {lab=IOVSS}
N 220 -2240 240 -2240 {lab=VSS}
N 220 -2240 220 -2210 {lab=VSS}
N 220 -2210 420 -2210 {lab=VSS}
N 320 -2240 400 -2240 {lab=VDD}
N 320 -2250 380 -2250 {lab=IOVDD}
N 220 -2250 240 -2250 {lab=IOVSS}
N 220 -2280 220 -2250 {lab=IOVSS}
N 220 -2280 360 -2280 {lab=IOVSS}
N 220 -2120 240 -2120 {lab=VSS}
N 220 -2120 220 -2090 {lab=VSS}
N 220 -2090 420 -2090 {lab=VSS}
N 320 -2120 400 -2120 {lab=VDD}
N 320 -2130 380 -2130 {lab=IOVDD}
N 220 -2140 240 -2140 {lab=IOVSS}
N 220 -2130 240 -2130 {lab=IOVSS}
N 220 -2140 220 -2130 {lab=IOVSS}
N 220 -2160 220 -2140 {lab=IOVSS}
N 220 -2160 360 -2160 {lab=IOVSS}
N 420 -2210 420 -2090 {lab=VSS}
N 400 -2240 400 -2120 {lab=VDD}
N 380 -2250 380 -2130 {lab=IOVDD}
N 360 -2280 360 -2160 {lab=IOVSS}
N 220 -450 240 -450 {lab=VSS}
N 220 -450 220 -420 {lab=VSS}
N 220 -420 420 -420 {lab=VSS}
N 320 -450 400 -450 {lab=VDD}
N 320 -460 380 -460 {lab=IOVDD}
N 220 -470 240 -470 {lab=IOVSS}
N 220 -460 240 -460 {lab=IOVSS}
N 220 -470 220 -460 {lab=IOVSS}
N 220 -490 220 -470 {lab=IOVSS}
N 220 -490 360 -490 {lab=IOVSS}
N 220 -570 240 -570 {lab=VSS}
N 220 -570 220 -540 {lab=VSS}
N 220 -540 420 -540 {lab=VSS}
N 320 -580 380 -580 {lab=IOVDD}
N 220 -580 240 -580 {lab=IOVSS}
N 420 -650 420 -540 {lab=VSS}
N 380 -710 380 -580 {lab=IOVDD}
N 360 -610 360 -490 {lab=IOVSS}
N 280 -1940 480 -1940 {lab=analog_io_res[12]}
N 140 -2030 280 -2030 {lab=analog_io[12]}
N 220 -1990 240 -1990 {lab=IOVSS}
N 220 -2040 220 -1990 {lab=IOVSS}
N 220 -2040 360 -2040 {lab=IOVSS}
N 360 -2160 360 -2040 {lab=IOVSS}
N 220 -1980 240 -1980 {lab=VSS}
N 220 -1980 220 -1930 {lab=VSS}
N 220 -1930 420 -1930 {lab=VSS}
N 420 -2090 420 -1930 {lab=VSS}
N 320 -2000 340 -2000 {lab=IOVDD}
N 380 -2130 380 -2000 {lab=IOVDD}
N 320 -1990 340 -1990 {lab=IOVDD}
N 340 -2000 340 -1990 {lab=IOVDD}
N 340 -2000 380 -2000 {lab=IOVDD}
N 320 -1980 400 -1980 {lab=VDD}
N 400 -2120 400 -1980 {lab=VDD}
N 280 -1780 480 -1780 {lab=analog_io_res[13]}
N 140 -1870 280 -1870 {lab=analog_io[13]}
N 220 -1830 240 -1830 {lab=IOVSS}
N 220 -1880 220 -1830 {lab=IOVSS}
N 220 -1880 360 -1880 {lab=IOVSS}
N 220 -1820 240 -1820 {lab=VSS}
N 220 -1820 220 -1770 {lab=VSS}
N 220 -1770 420 -1770 {lab=VSS}
N 320 -1840 340 -1840 {lab=IOVDD}
N 320 -1830 340 -1830 {lab=IOVDD}
N 340 -1840 340 -1830 {lab=IOVDD}
N 340 -1840 380 -1840 {lab=IOVDD}
N 320 -1820 400 -1820 {lab=VDD}
N 360 -2040 360 -1880 {lab=IOVSS}
N 420 -1930 420 -1770 {lab=VSS}
N 380 -2000 380 -1840 {lab=IOVDD}
N 400 -1980 400 -1820 {lab=VDD}
N 280 -1620 480 -1620 {lab=analog_io_res[14]}
N 140 -1710 280 -1710 {lab=analog_io[14]}
N 220 -1670 240 -1670 {lab=IOVSS}
N 220 -1720 220 -1670 {lab=IOVSS}
N 220 -1720 360 -1720 {lab=IOVSS}
N 220 -1660 240 -1660 {lab=VSS}
N 220 -1660 220 -1610 {lab=VSS}
N 220 -1610 420 -1610 {lab=VSS}
N 320 -1680 340 -1680 {lab=IOVDD}
N 320 -1670 340 -1670 {lab=IOVDD}
N 340 -1680 340 -1670 {lab=IOVDD}
N 340 -1680 380 -1680 {lab=IOVDD}
N 320 -1660 400 -1660 {lab=VDD}
N 360 -1880 360 -1720 {lab=IOVSS}
N 420 -1770 420 -1610 {lab=VSS}
N 380 -1840 380 -1680 {lab=IOVDD}
N 400 -1820 400 -1660 {lab=VDD}
N 280 -1460 480 -1460 {lab=analog_io_res[15]}
N 140 -1550 280 -1550 {lab=analog_io[15]}
N 220 -1510 240 -1510 {lab=IOVSS}
N 220 -1560 220 -1510 {lab=IOVSS}
N 220 -1560 360 -1560 {lab=IOVSS}
N 220 -1500 240 -1500 {lab=VSS}
N 220 -1500 220 -1450 {lab=VSS}
N 220 -1450 420 -1450 {lab=VSS}
N 320 -1520 340 -1520 {lab=IOVDD}
N 320 -1510 340 -1510 {lab=IOVDD}
N 340 -1520 340 -1510 {lab=IOVDD}
N 340 -1520 380 -1520 {lab=IOVDD}
N 320 -1500 400 -1500 {lab=VDD}
N 360 -1720 360 -1560 {lab=IOVSS}
N 420 -1610 420 -1450 {lab=VSS}
N 380 -1680 380 -1520 {lab=IOVDD}
N 400 -1660 400 -1500 {lab=VDD}
N 280 -1300 480 -1300 {lab=analog_io_res[16]}
N 140 -1390 280 -1390 {lab=analog_io[16]}
N 220 -1350 240 -1350 {lab=IOVSS}
N 220 -1400 220 -1350 {lab=IOVSS}
N 220 -1400 360 -1400 {lab=IOVSS}
N 220 -1340 240 -1340 {lab=VSS}
N 220 -1340 220 -1290 {lab=VSS}
N 220 -1290 420 -1290 {lab=VSS}
N 320 -1360 340 -1360 {lab=IOVDD}
N 320 -1350 340 -1350 {lab=IOVDD}
N 340 -1360 340 -1350 {lab=IOVDD}
N 340 -1360 380 -1360 {lab=IOVDD}
N 320 -1340 400 -1340 {lab=VDD}
N 360 -1560 360 -1400 {lab=IOVSS}
N 420 -1450 420 -1290 {lab=VSS}
N 380 -1520 380 -1360 {lab=IOVDD}
N 400 -1500 400 -1340 {lab=VDD}
N 280 -1140 480 -1140 {lab=analog_io_res[17]}
N 140 -1230 280 -1230 {lab=analog_io[17]}
N 220 -1190 240 -1190 {lab=IOVSS}
N 220 -1240 220 -1190 {lab=IOVSS}
N 220 -1240 360 -1240 {lab=IOVSS}
N 220 -1180 240 -1180 {lab=VSS}
N 220 -1180 220 -1130 {lab=VSS}
N 220 -1130 420 -1130 {lab=VSS}
N 320 -1200 340 -1200 {lab=IOVDD}
N 320 -1190 340 -1190 {lab=IOVDD}
N 340 -1200 340 -1190 {lab=IOVDD}
N 340 -1200 380 -1200 {lab=IOVDD}
N 320 -1180 400 -1180 {lab=VDD}
N 360 -1400 360 -1240 {lab=IOVSS}
N 420 -1290 420 -1130 {lab=VSS}
N 380 -1360 380 -1200 {lab=IOVDD}
N 400 -1340 400 -1180 {lab=VDD}
N 280 -980 480 -980 {lab=analog_io_res[18]}
N 140 -1070 280 -1070 {lab=analog_io[18]}
N 220 -1030 240 -1030 {lab=IOVSS}
N 220 -1080 220 -1030 {lab=IOVSS}
N 220 -1080 360 -1080 {lab=IOVSS}
N 220 -1020 240 -1020 {lab=VSS}
N 220 -1020 220 -970 {lab=VSS}
N 220 -970 420 -970 {lab=VSS}
N 320 -1040 340 -1040 {lab=IOVDD}
N 320 -1030 340 -1030 {lab=IOVDD}
N 340 -1040 340 -1030 {lab=IOVDD}
N 320 -1020 400 -1020 {lab=VDD}
N 360 -1240 360 -1080 {lab=IOVSS}
N 420 -1130 420 -970 {lab=VSS}
N 380 -1040 380 -880 {lab=IOVDD}
N 400 -1180 400 -1020 {lab=VDD}
N 280 -820 480 -820 {lab=analog_io_res[19]}
N 140 -910 280 -910 {lab=analog_io[19]}
N 220 -870 240 -870 {lab=IOVSS}
N 220 -920 220 -870 {lab=IOVSS}
N 220 -920 360 -920 {lab=IOVSS}
N 220 -860 240 -860 {lab=VSS}
N 220 -860 220 -810 {lab=VSS}
N 220 -810 420 -810 {lab=VSS}
N 320 -880 340 -880 {lab=IOVDD}
N 320 -870 340 -870 {lab=IOVDD}
N 340 -880 340 -870 {lab=IOVDD}
N 340 -880 380 -880 {lab=IOVDD}
N 320 -860 400 -860 {lab=VDD}
N 360 -1080 360 -920 {lab=IOVSS}
N 420 -970 420 -810 {lab=VSS}
N 400 -1020 400 -860 {lab=VDD}
N 280 -660 480 -660 {lab=digin_p2c[13]}
N 140 -750 280 -750 {lab=digin[13]}
N 220 -710 240 -710 {lab=IOVSS}
N 220 -720 220 -710 {lab=IOVSS}
N 220 -760 360 -760 {lab=IOVSS}
N 220 -700 240 -700 {lab=VSS}
N 220 -700 220 -650 {lab=VSS}
N 220 -650 420 -650 {lab=VSS}
N 320 -710 380 -710 {lab=IOVDD}
N 320 -700 400 -700 {lab=VDD}
N 360 -920 360 -760 {lab=IOVSS}
N 420 -810 420 -650 {lab=VSS}
N 380 -880 380 -710 {lab=IOVDD}
N 400 -860 400 -700 {lab=VDD}
N 200 -690 200 -560 {lab=SUB}
N 200 -560 240 -560 {lab=SUB}
N 200 -440 240 -440 {lab=SUB}
N 200 -690 240 -690 {lab=SUB}
N 200 -850 200 -690 {lab=SUB}
N 200 -850 240 -850 {lab=SUB}
N 200 -1010 200 -850 {lab=SUB}
N 200 -1010 240 -1010 {lab=SUB}
N 200 -1170 200 -1010 {lab=SUB}
N 200 -1170 240 -1170 {lab=SUB}
N 200 -1330 200 -1170 {lab=SUB}
N 200 -1330 240 -1330 {lab=SUB}
N 200 -1490 200 -1330 {lab=SUB}
N 200 -1490 240 -1490 {lab=SUB}
N 200 -1650 200 -1490 {lab=SUB}
N 200 -1650 240 -1650 {lab=SUB}
N 200 -1810 200 -1650 {lab=SUB}
N 200 -1810 240 -1810 {lab=SUB}
N 200 -1970 200 -1810 {lab=SUB}
N 200 -1970 240 -1970 {lab=SUB}
N 200 -2110 200 -1970 {lab=SUB}
N 200 -2110 240 -2110 {lab=SUB}
N 200 -2230 200 -2110 {lab=SUB}
N 200 -2230 240 -2230 {lab=SUB}
N 200 -2520 200 -2230 {lab=SUB}
N 320 -570 400 -570 {lab=VDD}
N 400 -700 400 -570 {lab=VDD}
N 340 -1040 380 -1040 {lab=IOVDD}
N 380 -1200 380 -1040 {lab=IOVDD}
N 420 -2400 420 -2210 {lab=VSS}
N 400 -2420 400 -2240 {lab=VDD}
N 380 -2440 380 -2250 {lab=IOVDD}
N 360 -2460 360 -2280 {lab=IOVSS}
N 200 -2620 200 -2520 {lab=SUB}
N 420 -540 420 -420 {lab=VSS}
N 380 -580 380 -460 {lab=IOVDD}
N 200 -560 200 -440 {lab=SUB}
N 400 -570 400 -450 {lab=VDD}
N 200 -2620 560 -2620 {lab=SUB}
N 200 -2680 200 -2620 {lab=SUB}
N 420 -2400 540 -2400 {lab=VSS}
N 420 -2500 420 -2400 {lab=VSS}
N 400 -2420 570 -2420 {lab=VDD}
N 400 -2530 400 -2420 {lab=VDD}
N 380 -2440 580 -2440 {lab=IOVDD}
N 380 -2540 380 -2440 {lab=IOVDD}
N 360 -2460 610 -2460 {lab=IOVSS}
N 360 -2580 360 -2460 {lab=IOVSS}
N 220 -590 220 -580 {lab=IOVSS}
N 220 -610 360 -610 {lab=IOVSS}
N 360 -760 360 -610 {lab=IOVSS}
N 220 -590 240 -590 {lab=IOVSS}
N 220 -610 220 -590 {lab=IOVSS}
N 200 -440 200 -80 {lab=SUB}
N 60 -80 200 -80 {lab=SUB}
N 360 -490 360 -240 {lab=IOVSS}
N 240 -240 360 -240 {lab=IOVSS}
N 380 -460 380 -260 {lab=IOVDD}
N 280 -260 380 -260 {lab=IOVDD}
N 400 -450 400 -280 {lab=VDD}
N 290 -280 400 -280 {lab=VDD}
N 420 -420 420 -300 {lab=VSS}
N 320 -300 420 -300 {lab=VSS}
N 1060 260 1260 260 {lab=IOVSS}
N 1260 260 1260 320 {lab=IOVSS}
N 1260 380 1260 420 {lab=SUB}
N 1120 420 1260 420 {lab=SUB}
N 1260 420 1360 420 {lab=SUB}
N 1360 380 1360 420 {lab=SUB}
N 1140 200 1360 200 {lab=VSS}
N 1360 200 1360 320 {lab=VSS}
N 710 -2600 710 -2580 {lab=IOVSS}
N 700 -2600 710 -2600 {lab=IOVSS}
N 2700 -700 2720 -700 {lab=IOVSS}
N 2720 -710 2720 -700 {lab=IOVSS}
N 2700 -860 2720 -860 {lab=IOVSS}
N 2720 -870 2720 -860 {lab=IOVSS}
N 2700 -1020 2720 -1020 {lab=IOVSS}
N 2720 -1030 2720 -1020 {lab=IOVSS}
N 2700 -1180 2720 -1180 {lab=IOVSS}
N 2720 -1190 2720 -1180 {lab=IOVSS}
N 2700 -1340 2720 -1340 {lab=IOVSS}
N 2720 -1350 2720 -1340 {lab=IOVSS}
N 2700 -1500 2720 -1500 {lab=IOVSS}
N 2720 -1510 2720 -1500 {lab=IOVSS}
N 2700 -1660 2720 -1660 {lab=IOVSS}
N 2720 -1670 2720 -1660 {lab=IOVSS}
N 2560 -1980 2560 -1830 {lab=IOVDD}
N 2700 -1820 2720 -1820 {lab=IOVSS}
N 2720 -1830 2720 -1820 {lab=IOVSS}
N 1480 -2440 1630 -2440 {lab=IOVDD}
N 1640 -2600 1640 -2580 {lab=IOVSS}
N 1630 -2600 1640 -2600 {lab=IOVSS}
N 1800 -2600 1800 -2580 {lab=IOVSS}
N 1790 -2600 1800 -2600 {lab=IOVSS}
N 1960 -2600 1960 -2580 {lab=IOVSS}
N 1950 -2600 1960 -2600 {lab=IOVSS}
N 2120 -2600 2120 -2580 {lab=IOVSS}
N 2110 -2600 2120 -2600 {lab=IOVSS}
N 1950 -2440 2110 -2440 {lab=IOVDD}
N 840 -2600 840 -2580 {lab=IOVSS}
N 830 -2600 840 -2600 {lab=IOVSS}
N 700 -2440 830 -2440 {lab=IOVDD}
N 220 -720 240 -720 {lab=IOVSS}
N 220 -760 220 -720 {lab=IOVSS}
N 2150 -2680 2150 -2540 {lab=digin[8]}
C {sg13g2_Corner_noptap.sym} 290 -160 0 0 {name=x5}
C {sg13g2_IOPadAnalog.sym} 840 -160 0 0 {name=x6}
C {sg13g2_IOPadVss.sym} 700 -160 0 0 {name=x10}
C {sg13g2_Filler4000.sym} 400 340 0 0 {name=x11[7:0]}
C {sg13g2_Filler1000.sym} 520 340 0 0 {name=x12[7:0]}
C {sg13g2_Filler400.sym} 640 340 0 0 {name=x13[7:0]}
C {sg13g2_Filler200.sym} 760 340 0 0 {name=x14[7:0]}
C {sg13g2_IOPadVdd.sym} 580 -160 0 0 {name=x15}
C {sg13g2_Filler4000.sym} 980 340 0 0 {name=x16[47:0]}
C {sg13g2_Filler400.sym} 1100 340 0 0 {name=x17[47:0]}
C {sg13g2_IOPadAnalog.sym} 1000 -160 0 0 {name=x1}
C {sg13g2_IOPadAnalog.sym} 1160 -160 0 0 {name=x2}
C {sg13g2_IOPadAnalog.sym} 1320 -160 0 0 {name=x3}
C {sg13g2_IOPadAnalog.sym} 1480 -160 0 0 {name=x4}
C {sg13g2_IOPadAnalog.sym} 1640 -160 0 0 {name=x11}
C {sg13g2_IOPadAnalog.sym} 1800 -160 0 0 {name=x12}
C {sg13g2_IOPadAnalog.sym} 1960 -160 0 0 {name=x13}
C {sg13g2_IOPadOut16mA.sym} 2110 -160 0 1 {name=x14}
C {sg13g2_IOPadIOVdd.sym} 2260 -160 0 0 {name=x16}
C {sg13g2_IOPadIOVss.sym} 2370 -160 0 0 {name=x17}
C {iopin.sym} 60 -300 0 1 {name=p1 lab=VSS}
C {iopin.sym} 60 -280 0 1 {name=p2 lab=VDD}
C {iopin.sym} 60 -260 0 1 {name=p3 lab=IOVDD}
C {iopin.sym} 60 -240 0 1 {name=p4 lab=IOVSS}
C {lab_pin.sym} 160 200 0 0 {name=p6 sig_type=std_logic lab=VSS}
C {lab_pin.sym} 160 220 0 0 {name=p7 sig_type=std_logic lab=VDD}
C {lab_pin.sym} 160 240 0 0 {name=p8 sig_type=std_logic lab=IOVDD}
C {lab_pin.sym} 160 260 0 0 {name=p9 sig_type=std_logic lab=IOVSS}
C {lab_pin.sym} 160 420 0 0 {name=p10 sig_type=std_logic lab=SUB}
C {lab_pin.sym} 1910 -20 3 0 {name=p12 sig_type=std_logic lab=analog_io[7]}
C {lab_pin.sym} 1750 -20 3 0 {name=p13 sig_type=std_logic lab=analog_io[6]}
C {lab_pin.sym} 1590 -20 3 0 {name=p14 sig_type=std_logic lab=analog_io[5]}
C {lab_pin.sym} 1430 -20 3 0 {name=p15 sig_type=std_logic lab=analog_io[4]}
C {lab_pin.sym} 1270 -20 3 0 {name=p16 sig_type=std_logic lab=analog_io[3]}
C {lab_pin.sym} 1110 -20 3 0 {name=p17 sig_type=std_logic lab=analog_io[2]}
C {lab_pin.sym} 950 -20 3 0 {name=p18 sig_type=std_logic lab=analog_io[1]}
C {lab_pin.sym} 790 -20 3 0 {name=p19 sig_type=std_logic lab=analog_io[0]}
C {lab_pin.sym} 2070 -20 3 0 {name=p20 sig_type=std_logic lab=digout}
C {sg13g2_Corner_noptap.sym} 2660 -170 3 0 {name=x7}
C {sg13g2_IOPadIn.sym} 2660 -720 3 0 {name=x8}
C {sg13g2_IOPadVss.sym} 2660 -580 3 0 {name=x9}
C {sg13g2_IOPadVdd.sym} 2660 -460 3 0 {name=x18}
C {sg13g2_IOPadAnalog.sym} 2660 -2000 3 0 {name=x26}
C {sg13g2_IOPadIOVdd.sym} 2660 -2140 3 0 {name=x27}
C {sg13g2_IOPadIOVss.sym} 2660 -2250 3 0 {name=x28}
C {lab_pin.sym} 2800 -1950 2 0 {name=p26 sig_type=std_logic lab=analog_io[8]}
C {lab_pin.sym} 2800 -1790 2 0 {name=p27 sig_type=std_logic lab=digin[7]}
C {lab_pin.sym} 2800 -1630 2 0 {name=p28 sig_type=std_logic lab=digin[6]}
C {lab_pin.sym} 2800 -1470 2 0 {name=p29 sig_type=std_logic lab=digin[5]}
C {lab_pin.sym} 2800 -1310 2 0 {name=p30 sig_type=std_logic lab=digin[4]}
C {lab_pin.sym} 2800 -1150 2 0 {name=p31 sig_type=std_logic lab=digin[3]}
C {lab_pin.sym} 2800 -990 2 0 {name=p32 sig_type=std_logic lab=digin[2]}
C {lab_pin.sym} 2800 -830 2 0 {name=p33 sig_type=std_logic lab=digin[1]}
C {lab_pin.sym} 2800 -670 2 0 {name=p34 sig_type=std_logic lab=digin[0]}
C {noconn.sym} 2520 -20 3 0 {name=l19}
C {noconn.sym} 2540 -20 3 0 {name=l20}
C {noconn.sym} 2560 -20 3 0 {name=l21}
C {noconn.sym} 2580 -20 3 0 {name=l22}
C {noconn.sym} 2740 -20 3 0 {name=l23}
C {lab_pin.sym} 60 -80 0 0 {name=p5 sig_type=std_logic lab=SUB}
C {sg13g2_Corner_noptap.sym} 2650 -2540 2 0 {name=x29}
C {sg13g2_IOPadIn.sym} 2100 -2540 2 0 {name=x30}
C {sg13g2_IOPadIOVdd.sym} 2240 -2540 2 0 {name=x31}
C {sg13g2_IOPadIOVss.sym} 2360 -2540 2 0 {name=x32}
C {sg13g2_IOPadRF.sym} 1460 -2540 2 0 {name=x36}
C {sg13g2_IOPadAnalog.sym} 1300 -2540 2 0 {name=x37}
C {sg13g2_IOPadAnalog.sym} 1140 -2540 2 0 {name=x38}
C {sg13g2_IOPadAnalog.sym} 980 -2540 2 0 {name=x39}
C {sg13g2_IOPadIn.sym} 820 -2540 2 0 {name=x40}
C {sg13g2_IOPadVdd.sym} 570 -2540 2 0 {name=x41}
C {sg13g2_IOPadVss.sym} 690 -2540 2 0 {name=x42}
C {lab_pin.sym} 870 -2680 1 0 {name=p21 sig_type=std_logic lab=digin[12]}
C {lab_pin.sym} 1030 -2680 1 0 {name=p22 sig_type=std_logic lab=analog_io[11]}
C {lab_pin.sym} 1190 -2680 1 0 {name=p23 sig_type=std_logic lab=analog_io[10]}
C {lab_pin.sym} 1350 -2680 1 0 {name=p24 sig_type=std_logic lab=analog_io[9]}
C {lab_pin.sym} 1510 -2680 1 0 {name=p25 sig_type=std_logic lab=rf}
C {lab_pin.sym} 1670 -2680 1 0 {name=p35 sig_type=std_logic lab=digin[11]}
C {lab_pin.sym} 1830 -2680 1 0 {name=p36 sig_type=std_logic lab=digin[10]}
C {lab_pin.sym} 1990 -2680 1 0 {name=p37 sig_type=std_logic lab=digin[9]}
C {noconn.sym} 2800 -2400 2 0 {name=l33}
C {noconn.sym} 2800 -2420 2 0 {name=l34}
C {noconn.sym} 2800 -2440 2 0 {name=l35}
C {noconn.sym} 2800 -2460 2 0 {name=l36}
C {noconn.sym} 2800 -2620 2 0 {name=l37}
C {sg13g2_Corner_noptap.sym} 280 -2530 1 0 {name=x43}
C {sg13g2_IOPadAnalog.sym} 280 -1980 1 0 {name=x44}
C {sg13g2_IOPadIOVdd.sym} 280 -2120 1 0 {name=x45}
C {sg13g2_IOPadIOVss.sym} 280 -2240 1 0 {name=x46}
C {sg13g2_IOPadAnalog.sym} 280 -1820 1 0 {name=x47}
C {sg13g2_IOPadAnalog.sym} 280 -1660 1 0 {name=x48}
C {sg13g2_IOPadAnalog.sym} 280 -1500 1 0 {name=x49}
C {sg13g2_IOPadAnalog.sym} 280 -1340 1 0 {name=x50}
C {sg13g2_IOPadAnalog.sym} 280 -1180 1 0 {name=x51}
C {sg13g2_IOPadAnalog.sym} 280 -1020 1 0 {name=x52}
C {sg13g2_IOPadAnalog.sym} 280 -860 1 0 {name=x53}
C {sg13g2_IOPadIn.sym} 280 -700 1 0 {name=x54}
C {sg13g2_IOPadVdd.sym} 280 -450 1 0 {name=x55}
C {sg13g2_IOPadVss.sym} 280 -570 1 0 {name=x56}
C {lab_pin.sym} 140 -750 0 0 {name=p39 sig_type=std_logic lab=digin[13]}
C {lab_pin.sym} 140 -910 0 0 {name=p40 sig_type=std_logic lab=analog_io[19]}
C {lab_pin.sym} 140 -1070 0 0 {name=p41 sig_type=std_logic lab=analog_io[18]}
C {lab_pin.sym} 140 -1230 0 0 {name=p42 sig_type=std_logic lab=analog_io[17]}
C {lab_pin.sym} 140 -1390 0 0 {name=p43 sig_type=std_logic lab=analog_io[16]}
C {lab_pin.sym} 140 -1550 0 0 {name=p44 sig_type=std_logic lab=analog_io[15]}
C {lab_pin.sym} 140 -1710 0 0 {name=p45 sig_type=std_logic lab=analog_io[14]}
C {lab_pin.sym} 140 -1870 0 0 {name=p46 sig_type=std_logic lab=analog_io[13]}
C {lab_pin.sym} 140 -2030 0 0 {name=p47 sig_type=std_logic lab=analog_io[12]}
C {noconn.sym} 420 -2680 1 0 {name=l47}
C {noconn.sym} 400 -2680 1 0 {name=l48}
C {noconn.sym} 380 -2680 1 0 {name=l49}
C {noconn.sym} 360 -2680 1 0 {name=l50}
C {noconn.sym} 200 -2680 1 0 {name=l51}
C {sg13g2_pr/ptap1.sym} 1360 350 0 0 {name=R4
model=ptap1
spiceprefix=X
w=7.27e-6
l=7.27e-6
lvs_format="tcleval(@name @pinlist @model A=52.7736p P=338.816u )"
}
C {sg13g2_pr/ptap1.sym} 1260 350 0 0 {name=R1
model=ptap1
spiceprefix=X
w=201.69e-6
l=201.69e-6
lvs_format="tcleval(@name @pinlist @model A=40674.96p P=3929.688u )"
}
C {sg13g2_IOPadIn.sym} 2660 -880 3 0 {name=x19}
C {sg13g2_IOPadIn.sym} 2660 -1040 3 0 {name=x20}
C {sg13g2_IOPadIn.sym} 2660 -1200 3 0 {name=x21}
C {sg13g2_IOPadIn.sym} 2660 -1360 3 0 {name=x22}
C {sg13g2_IOPadIn.sym} 2660 -1520 3 0 {name=x23}
C {sg13g2_IOPadIn.sym} 2660 -1680 3 0 {name=x24}
C {sg13g2_IOPadIn.sym} 2660 -1840 3 0 {name=x25}
C {sg13g2_IOPadIn.sym} 1940 -2540 2 0 {name=x33}
C {sg13g2_IOPadIn.sym} 1780 -2540 2 0 {name=x34}
C {sg13g2_IOPadIn.sym} 1620 -2540 2 0 {name=x35}
C {lab_pin.sym} 2150 -2680 1 0 {name=p38 sig_type=std_logic lab=digin[8]}
C {iopin.sym} -370 -2590 0 1 {name=p48 lab=digout}
C {iopin.sym} -370 -2570 0 1 {name=p50 lab=rf}
C {lab_pin.sym} 2000 -360 3 1 {name=p51 sig_type=std_logic lab=analog_io_res[7]}
C {lab_pin.sym} 1840 -360 3 1 {name=p52 sig_type=std_logic lab=analog_io_res[6]}
C {lab_pin.sym} 1680 -360 3 1 {name=p53 sig_type=std_logic lab=analog_io_res[5]}
C {lab_pin.sym} 1520 -360 3 1 {name=p54 sig_type=std_logic lab=analog_io_res[4]}
C {lab_pin.sym} 1360 -360 3 1 {name=p55 sig_type=std_logic lab=analog_io_res[3]}
C {lab_pin.sym} 1200 -360 3 1 {name=p56 sig_type=std_logic lab=analog_io_res[2]}
C {lab_pin.sym} 1040 -360 3 1 {name=p57 sig_type=std_logic lab=analog_io_res[1]}
C {lab_pin.sym} 880 -360 3 1 {name=p58 sig_type=std_logic lab=analog_io_res[0]}
C {lab_pin.sym} 2160 -360 3 1 {name=p59 sig_type=std_logic lab=digout_c2p}
C {lab_pin.sym} 2460 -2040 2 1 {name=p60 sig_type=std_logic lab=analog_io_res[8]}
C {lab_pin.sym} 2460 -1880 2 1 {name=p61 sig_type=std_logic lab=digin_p2c[7]}
C {lab_pin.sym} 2460 -1720 2 1 {name=p62 sig_type=std_logic lab=digin_p2c[6]}
C {lab_pin.sym} 2460 -1560 2 1 {name=p63 sig_type=std_logic lab=digin_p2c[5]}
C {lab_pin.sym} 2460 -1400 2 1 {name=p64 sig_type=std_logic lab=digin_p2c[4]}
C {lab_pin.sym} 2460 -1240 2 1 {name=p65 sig_type=std_logic lab=digin_p2c[3]}
C {lab_pin.sym} 2460 -1080 2 1 {name=p66 sig_type=std_logic lab=digin_p2c[2]}
C {lab_pin.sym} 2460 -920 2 1 {name=p67 sig_type=std_logic lab=digin_p2c[1]}
C {lab_pin.sym} 2460 -760 2 1 {name=p68 sig_type=std_logic lab=digin_p2c[0]}
C {lab_pin.sym} 780 -2340 1 1 {name=p69 sig_type=std_logic lab=digin_p2c[12]}
C {lab_pin.sym} 940 -2340 1 1 {name=p70 sig_type=std_logic lab=analog_io_res[11]}
C {lab_pin.sym} 1100 -2340 1 1 {name=p71 sig_type=std_logic lab=analog_io_res[10]}
C {lab_pin.sym} 1260 -2340 1 1 {name=p72 sig_type=std_logic lab=analog_io_res[9]}
C {lab_pin.sym} 1580 -2340 1 1 {name=p74 sig_type=std_logic lab=digin_p2c[11]}
C {lab_pin.sym} 1740 -2340 1 1 {name=p75 sig_type=std_logic lab=digin_p2c[10]}
C {lab_pin.sym} 1900 -2340 1 1 {name=p76 sig_type=std_logic lab=digin_p2c[9]}
C {lab_pin.sym} 2060 -2340 1 1 {name=p77 sig_type=std_logic lab=digin_p2c[8]}
C {lab_pin.sym} 480 -660 0 1 {name=p78 sig_type=std_logic lab=digin_p2c[13]}
C {lab_pin.sym} 480 -820 0 1 {name=p79 sig_type=std_logic lab=analog_io_res[19]}
C {lab_pin.sym} 480 -980 0 1 {name=p80 sig_type=std_logic lab=analog_io_res[18]}
C {lab_pin.sym} 480 -1140 0 1 {name=p81 sig_type=std_logic lab=analog_io_res[17]}
C {lab_pin.sym} 480 -1300 0 1 {name=p82 sig_type=std_logic lab=analog_io_res[16]}
C {lab_pin.sym} 480 -1460 0 1 {name=p83 sig_type=std_logic lab=analog_io_res[15]}
C {lab_pin.sym} 480 -1620 0 1 {name=p84 sig_type=std_logic lab=analog_io_res[14]}
C {lab_pin.sym} 480 -1780 0 1 {name=p85 sig_type=std_logic lab=analog_io_res[13]}
C {lab_pin.sym} 480 -1940 0 1 {name=p86 sig_type=std_logic lab=analog_io_res[12]}
C {iopin.sym} -140 -2015 0 1 {name=p88 lab=digin_p2c[13]}
C {iopin.sym} -110 -2590 0 1 {name=p89 lab=digout_c2p}
C {iopin.sym} -370 -2450 0 1 {name=p73 lab=analog_io[19]}
C {iopin.sym} -370 -2430 0 1 {name=p49 lab=analog_io[18]}
C {iopin.sym} -370 -2410 0 1 {name=p90 lab=analog_io[17]}
C {iopin.sym} -370 -2390 0 1 {name=p91 lab=analog_io[16]}
C {iopin.sym} -370 -2370 0 1 {name=p92 lab=analog_io[15]}
C {iopin.sym} -370 -2350 0 1 {name=p93 lab=analog_io[14]}
C {iopin.sym} -370 -2330 0 1 {name=p94 lab=analog_io[13]}
C {iopin.sym} -370 -2310 0 1 {name=p95 lab=analog_io[12]}
C {iopin.sym} -370 -2290 0 1 {name=p96 lab=analog_io[11]}
C {iopin.sym} -370 -2270 0 1 {name=p97 lab=analog_io[10]}
C {iopin.sym} -370 -2250 0 1 {name=p98 lab=analog_io[9]}
C {iopin.sym} -370 -2210 0 1 {name=p99 lab=analog_io[7]}
C {iopin.sym} -370 -2190 0 1 {name=p100 lab=analog_io[6]}
C {iopin.sym} -370 -2170 0 1 {name=p101 lab=analog_io[5]}
C {iopin.sym} -370 -2150 0 1 {name=p102 lab=analog_io[4]}
C {iopin.sym} -370 -2130 0 1 {name=p103 lab=analog_io[3]}
C {iopin.sym} -370 -2110 0 1 {name=p104 lab=analog_io[2]}
C {iopin.sym} -370 -2090 0 1 {name=p105 lab=analog_io[1]}
C {iopin.sym} -370 -2230 0 1 {name=p106 lab=analog_io[8]}
C {iopin.sym} -370 -2070 0 1 {name=p107 lab=analog_io[0]}
C {iopin.sym} -140 -2450 0 1 {name=p108 lab=analog_io_res[19]}
C {iopin.sym} -140 -2430 0 1 {name=p109 lab=analog_io_res[18]}
C {iopin.sym} -140 -2410 0 1 {name=p110 lab=analog_io_res[17]}
C {iopin.sym} -140 -2390 0 1 {name=p111 lab=analog_io_res[16]}
C {iopin.sym} -140 -2370 0 1 {name=p112 lab=analog_io_res[15]}
C {iopin.sym} -140 -2350 0 1 {name=p113 lab=analog_io_res[14]}
C {iopin.sym} -140 -2330 0 1 {name=p114 lab=analog_io_res[13]}
C {iopin.sym} -140 -2310 0 1 {name=p115 lab=analog_io_res[12]}
C {iopin.sym} -140 -2290 0 1 {name=p116 lab=analog_io_res[11]}
C {iopin.sym} -140 -2270 0 1 {name=p117 lab=analog_io_res[10]}
C {iopin.sym} -140 -2250 0 1 {name=p118 lab=analog_io_res[9]}
C {iopin.sym} -140 -2210 0 1 {name=p119 lab=analog_io_res[7]}
C {iopin.sym} -140 -2190 0 1 {name=p120 lab=analog_io_res[6]}
C {iopin.sym} -140 -2170 0 1 {name=p121 lab=analog_io_res[5]}
C {iopin.sym} -140 -2150 0 1 {name=p122 lab=analog_io_res[4]}
C {iopin.sym} -140 -2130 0 1 {name=p123 lab=analog_io_res[3]}
C {iopin.sym} -140 -2110 0 1 {name=p124 lab=analog_io_res[2]}
C {iopin.sym} -140 -2090 0 1 {name=p125 lab=analog_io_res[1]}
C {iopin.sym} -140 -2230 0 1 {name=p126 lab=analog_io_res[8]}
C {iopin.sym} -140 -2070 0 1 {name=p127 lab=analog_io_res[0]}
C {iopin.sym} -370 -2015 0 1 {name=p87 lab=digin[13]}
C {iopin.sym} -370 -1995 0 1 {name=p128 lab=digin[12]}
C {iopin.sym} -370 -1975 0 1 {name=p129 lab=digin[11]}
C {iopin.sym} -370 -1955 0 1 {name=p130 lab=digin[10]}
C {iopin.sym} -370 -1935 0 1 {name=p131 lab=digin[9]}
C {iopin.sym} -370 -1915 0 1 {name=p132 lab=digin[8]}
C {iopin.sym} -370 -1895 0 1 {name=p133 lab=digin[7]}
C {iopin.sym} -370 -1875 0 1 {name=p134 lab=digin[6]}
C {iopin.sym} -370 -1855 0 1 {name=p135 lab=digin[5]}
C {iopin.sym} -370 -1835 0 1 {name=p136 lab=digin[4]}
C {iopin.sym} -370 -1815 0 1 {name=p137 lab=digin[3]}
C {iopin.sym} -370 -1795 0 1 {name=p138 lab=digin[2]}
C {iopin.sym} -370 -1775 0 1 {name=p139 lab=digin[1]}
C {iopin.sym} -370 -1755 0 1 {name=p140 lab=digin[0]}
C {iopin.sym} -140 -1995 0 1 {name=p11 lab=digin_p2c[12]}
C {iopin.sym} -140 -1975 0 1 {name=p141 lab=digin_p2c[11]}
C {iopin.sym} -140 -1955 0 1 {name=p142 lab=digin_p2c[10]}
C {iopin.sym} -140 -1935 0 1 {name=p143 lab=digin_p2c[9]}
C {iopin.sym} -140 -1915 0 1 {name=p144 lab=digin_p2c[8]}
C {iopin.sym} -140 -1895 0 1 {name=p145 lab=digin_p2c[7]}
C {iopin.sym} -140 -1875 0 1 {name=p146 lab=digin_p2c[6]}
C {iopin.sym} -140 -1855 0 1 {name=p147 lab=digin_p2c[5]}
C {iopin.sym} -140 -1835 0 1 {name=p148 lab=digin_p2c[4]}
C {iopin.sym} -140 -1815 0 1 {name=p149 lab=digin_p2c[3]}
C {iopin.sym} -140 -1795 0 1 {name=p150 lab=digin_p2c[2]}
C {iopin.sym} -140 -1775 0 1 {name=p151 lab=digin_p2c[1]}
C {iopin.sym} -140 -1755 0 1 {name=p152 lab=digin_p2c[0]}
C {iopin.sym} 60 -100 0 1 {name=p153 lab=SUB}
